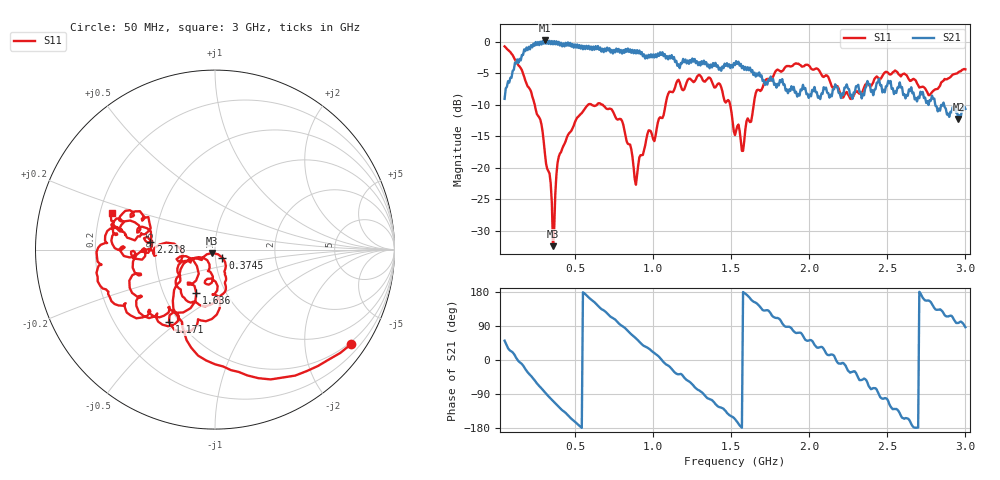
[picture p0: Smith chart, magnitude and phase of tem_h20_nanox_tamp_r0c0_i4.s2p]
! nanovna_capture.py 2026-10-26T21:54:50+0900
! NanoVNA-F_V2 fw 0.6.0 SN 4A3639384505514B
! cal: load open short thru cal'ed  over 50000000-3000000000 Hz, 201 points
! points 401, avg 4
! TEM h=20, tampered Nano X, 0 deg, centred, interleaved run T4
# HZ S RI R 50
! S12 and S22 are not measured (written as 0)
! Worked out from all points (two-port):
!   401 points, 50 MHz to 3 GHz, reference 50 ohm
!   highest |S21| = 0.25 dB at 308.1 MHz (marker M1); lowest = -12.2 dB at 2.956 GHz (marker M2)
!   |S21| within 3 dB of the highest: 154.8 MHz to 1.097 GHz (942.3 MHz wide, 151 % of centre); 1.097 GHz to 1.138 GHz (40.1 MHz wide, 3.59 % of centre) (the widest 2 of 6)
!   lowest |S11| = -32.5 dB at 359.8 MHz (marker M3), VSWR 1.05, Z = 48.5 - j1.81 ohm
!   |S11| at or under -10 dB: 242.8 MHz to 583.8 MHz (341 MHz wide, 82.5 % of centre); 678.6 MHz to 1.08 GHz (401.6 MHz wide, 45.7 % of centre); 1.494 GHz to 1.645 GHz (150.5 MHz wide, 9.59 % of centre) (the widest 3 of 4)
!   S12 and S22 are empty: the file has one direction only
!   S11 on the Smith chart (normalised r, x): 50 MHz: 0.44, -3.14; 374.5 MHz: 1.08, -0.10; 1.171 GHz: 0.44, -0.46; 1.636 GHz: 0.73, -0.38; 2.218 GHz: 0.47, +0.05; 3 GHz: 0.25, +0.16
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5e7  0.7586 -0.5266  0.2226 0.2741  0 0  0 0
1.75375e8  -0.1582 -0.5047  0.8274 -0.2826  0 0  0 0
3.08125e8  -0.12 -0.0489  0.0827 -1.026  0 0  0 0
3.5975e8  -0.0147 -0.0187  -0.2955 -0.9117  0 0  0 0
3.745e8  0.0418 -0.0455  -0.3953 -0.8745  0 0  0 0
4.04e8  0.0533 -0.118  -0.564 -0.7493  0 0  0 0
5.44125e8  0.0144 -0.2717  -0.9372 -0.0175  0 0  0 0
6.62125e8  -0.1622 -0.2809  -0.6632 0.6156  0 0  0 0
7.80125e8  -0.1969 -0.1429  -0.1069 0.8754  0 0  0 0
8.9075e8  -0.0433 -0.059  0.4388 0.6827  0 0  0 0
1.03825e9  -0.00119 -0.2459  0.7667 0.1173  0 0  0 0
1.171e9  -0.2567 -0.4043  0.4927 -0.3755  0 0  0 0
1.325875e9  -0.4135 -0.2561  -0.00902 -0.7117  0 0  0 0
1.525e9  -0.1793 -0.0292  -0.5981 -0.2667  0 0  0 0
1.635625e9  -0.1046 -0.2424  -0.5484 0.2397  0 0  0 0
1.783125e9  -0.4378 -0.3828  -0.17 0.4342  0 0  0 0
2.019125e9  -0.6051 0.0376  0.2654 0.321  0 0  0 0
2.21825e9  -0.3596 0.044  0.3765 -0.0516  0 0  0 0
2.51325e9  -0.5467 0.0901  -0.2122 -0.4201  0 0  0 0
2.712375e9  -0.3996 0.1789  -0.4017 0.028  0 0  0 0
2.95575e9  -0.5605 0.1314  -0.0328 0.242  0 0  0 0
3e9  -0.5716 0.2025  0.0177 0.2932  0 0  0 0
